One B-rep face of a CAD part: STEP entity #38742.
In plain terms, the planar face has unit normal (0, 0, 1).
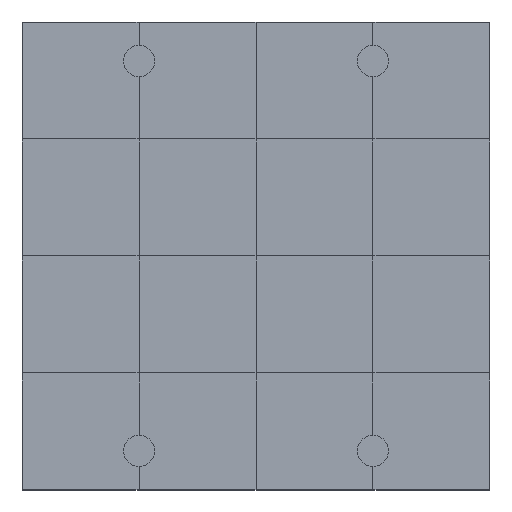
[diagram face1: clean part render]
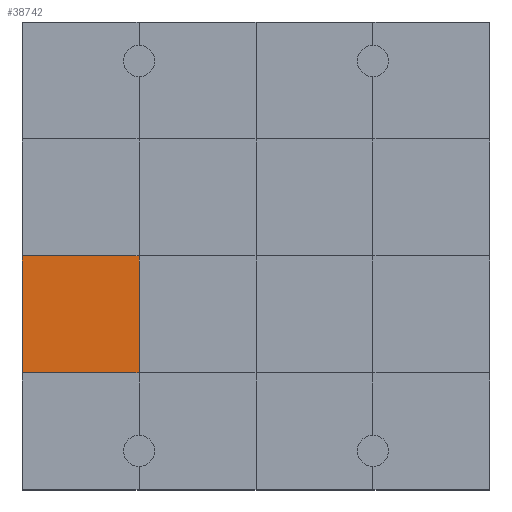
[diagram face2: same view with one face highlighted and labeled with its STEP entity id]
Its self-contained STEP definition (entity closure, numbers rounded to 3 decimals):
#38292 = VERTEX_POINT('',#38293);
#38293 = CARTESIAN_POINT('',(0.,3.,1.2));
#38307 = PLANE('',#38308);
#38308 = AXIS2_PLACEMENT_3D('',#38309,#38310,#38311);
#38309 = CARTESIAN_POINT('',(0.,3.,0.));
#38310 = DIRECTION('',(1.,0.,-0.));
#38311 = DIRECTION('',(0.,0.,1.));
#38333 = PLANE('',#38334);
#38334 = AXIS2_PLACEMENT_3D('',#38335,#38336,#38337);
#38335 = CARTESIAN_POINT('',(0.,0.,1.2));
#38336 = DIRECTION('',(0.,0.,1.));
#38337 = DIRECTION('',(1.,0.,-0.));
#38484 = VERTEX_POINT('',#38485);
#38485 = CARTESIAN_POINT('',(3.,3.,1.2));
#38506 = EDGE_CURVE('',#38292,#38484,#38507,.T.);
#38507 = SURFACE_CURVE('',#38508,(#38512,#38519),.PCURVE_S1.);
#38508 = LINE('',#38509,#38510);
#38509 = CARTESIAN_POINT('',(0.,3.,1.2));
#38510 = VECTOR('',#38511,1.);
#38511 = DIRECTION('',(1.,0.,-0.));
#38512 = PCURVE('',#38333,#38513);
#38513 = DEFINITIONAL_REPRESENTATION('',(#38514),#38518);
#38514 = LINE('',#38515,#38516);
#38515 = CARTESIAN_POINT('',(0.,3.));
#38516 = VECTOR('',#38517,1.);
#38517 = DIRECTION('',(1.,0.));
#38518 = ( GEOMETRIC_REPRESENTATION_CONTEXT(2) 
PARAMETRIC_REPRESENTATION_CONTEXT() REPRESENTATION_CONTEXT('2D SPACE',''
  ) );
#38519 = PCURVE('',#38520,#38525);
#38520 = PLANE('',#38521);
#38521 = AXIS2_PLACEMENT_3D('',#38522,#38523,#38524);
#38522 = CARTESIAN_POINT('',(0.,3.,1.2));
#38523 = DIRECTION('',(0.,0.,1.));
#38524 = DIRECTION('',(1.,0.,-0.));
#38525 = DEFINITIONAL_REPRESENTATION('',(#38526),#38530);
#38526 = LINE('',#38527,#38528);
#38527 = CARTESIAN_POINT('',(0.,0.));
#38528 = VECTOR('',#38529,1.);
#38529 = DIRECTION('',(1.,0.));
#38530 = ( GEOMETRIC_REPRESENTATION_CONTEXT(2) 
PARAMETRIC_REPRESENTATION_CONTEXT() REPRESENTATION_CONTEXT('2D SPACE',''
  ) );
#38565 = VERTEX_POINT('',#38566);
#38566 = CARTESIAN_POINT('',(0.,6.,1.2));
#38592 = EDGE_CURVE('',#38292,#38565,#38593,.T.);
#38593 = SURFACE_CURVE('',#38594,(#38598,#38605),.PCURVE_S1.);
#38594 = LINE('',#38595,#38596);
#38595 = CARTESIAN_POINT('',(0.,3.,1.2));
#38596 = VECTOR('',#38597,1.);
#38597 = DIRECTION('',(-0.,1.,0.));
#38598 = PCURVE('',#38307,#38599);
#38599 = DEFINITIONAL_REPRESENTATION('',(#38600),#38604);
#38600 = LINE('',#38601,#38602);
#38601 = CARTESIAN_POINT('',(1.2,0.));
#38602 = VECTOR('',#38603,1.);
#38603 = DIRECTION('',(0.,-1.));
#38604 = ( GEOMETRIC_REPRESENTATION_CONTEXT(2) 
PARAMETRIC_REPRESENTATION_CONTEXT() REPRESENTATION_CONTEXT('2D SPACE',''
  ) );
#38605 = PCURVE('',#38520,#38606);
#38606 = DEFINITIONAL_REPRESENTATION('',(#38607),#38611);
#38607 = LINE('',#38608,#38609);
#38608 = CARTESIAN_POINT('',(0.,0.));
#38609 = VECTOR('',#38610,1.);
#38610 = DIRECTION('',(0.,1.));
#38611 = ( GEOMETRIC_REPRESENTATION_CONTEXT(2) 
PARAMETRIC_REPRESENTATION_CONTEXT() REPRESENTATION_CONTEXT('2D SPACE',''
  ) );
#38742 = ADVANCED_FACE('',(#38743),#38520,.T.);
#38743 = FACE_BOUND('',#38744,.T.);
#38744 = EDGE_LOOP('',(#38745,#38746,#38747,#38775));
#38745 = ORIENTED_EDGE('',*,*,#38592,.F.);
#38746 = ORIENTED_EDGE('',*,*,#38506,.T.);
#38747 = ORIENTED_EDGE('',*,*,#38748,.T.);
#38748 = EDGE_CURVE('',#38484,#38749,#38751,.T.);
#38749 = VERTEX_POINT('',#38750);
#38750 = CARTESIAN_POINT('',(3.,6.,1.2));
#38751 = SURFACE_CURVE('',#38752,(#38756,#38763),.PCURVE_S1.);
#38752 = LINE('',#38753,#38754);
#38753 = CARTESIAN_POINT('',(3.,3.,1.2));
#38754 = VECTOR('',#38755,1.);
#38755 = DIRECTION('',(-0.,1.,0.));
#38756 = PCURVE('',#38520,#38757);
#38757 = DEFINITIONAL_REPRESENTATION('',(#38758),#38762);
#38758 = LINE('',#38759,#38760);
#38759 = CARTESIAN_POINT('',(3.,0.));
#38760 = VECTOR('',#38761,1.);
#38761 = DIRECTION('',(0.,1.));
#38762 = ( GEOMETRIC_REPRESENTATION_CONTEXT(2) 
PARAMETRIC_REPRESENTATION_CONTEXT() REPRESENTATION_CONTEXT('2D SPACE',''
  ) );
#38763 = PCURVE('',#38764,#38769);
#38764 = PLANE('',#38765);
#38765 = AXIS2_PLACEMENT_3D('',#38766,#38767,#38768);
#38766 = CARTESIAN_POINT('',(3.,3.,1.2));
#38767 = DIRECTION('',(0.,0.,1.));
#38768 = DIRECTION('',(1.,0.,-0.));
#38769 = DEFINITIONAL_REPRESENTATION('',(#38770),#38774);
#38770 = LINE('',#38771,#38772);
#38771 = CARTESIAN_POINT('',(0.,0.));
#38772 = VECTOR('',#38773,1.);
#38773 = DIRECTION('',(0.,1.));
#38774 = ( GEOMETRIC_REPRESENTATION_CONTEXT(2) 
PARAMETRIC_REPRESENTATION_CONTEXT() REPRESENTATION_CONTEXT('2D SPACE',''
  ) );
#38775 = ORIENTED_EDGE('',*,*,#38776,.F.);
#38776 = EDGE_CURVE('',#38565,#38749,#38777,.T.);
#38777 = SURFACE_CURVE('',#38778,(#38782,#38789),.PCURVE_S1.);
#38778 = LINE('',#38779,#38780);
#38779 = CARTESIAN_POINT('',(0.,6.,1.2));
#38780 = VECTOR('',#38781,1.);
#38781 = DIRECTION('',(1.,0.,-0.));
#38782 = PCURVE('',#38520,#38783);
#38783 = DEFINITIONAL_REPRESENTATION('',(#38784),#38788);
#38784 = LINE('',#38785,#38786);
#38785 = CARTESIAN_POINT('',(0.,3.));
#38786 = VECTOR('',#38787,1.);
#38787 = DIRECTION('',(1.,0.));
#38788 = ( GEOMETRIC_REPRESENTATION_CONTEXT(2) 
PARAMETRIC_REPRESENTATION_CONTEXT() REPRESENTATION_CONTEXT('2D SPACE',''
  ) );
#38789 = PCURVE('',#38790,#38795);
#38790 = PLANE('',#38791);
#38791 = AXIS2_PLACEMENT_3D('',#38792,#38793,#38794);
#38792 = CARTESIAN_POINT('',(0.,6.,1.2));
#38793 = DIRECTION('',(0.,0.,1.));
#38794 = DIRECTION('',(1.,0.,-0.));
#38795 = DEFINITIONAL_REPRESENTATION('',(#38796),#38800);
#38796 = LINE('',#38797,#38798);
#38797 = CARTESIAN_POINT('',(0.,0.));
#38798 = VECTOR('',#38799,1.);
#38799 = DIRECTION('',(1.,0.));
#38800 = ( GEOMETRIC_REPRESENTATION_CONTEXT(2) 
PARAMETRIC_REPRESENTATION_CONTEXT() REPRESENTATION_CONTEXT('2D SPACE',''
  ) );
